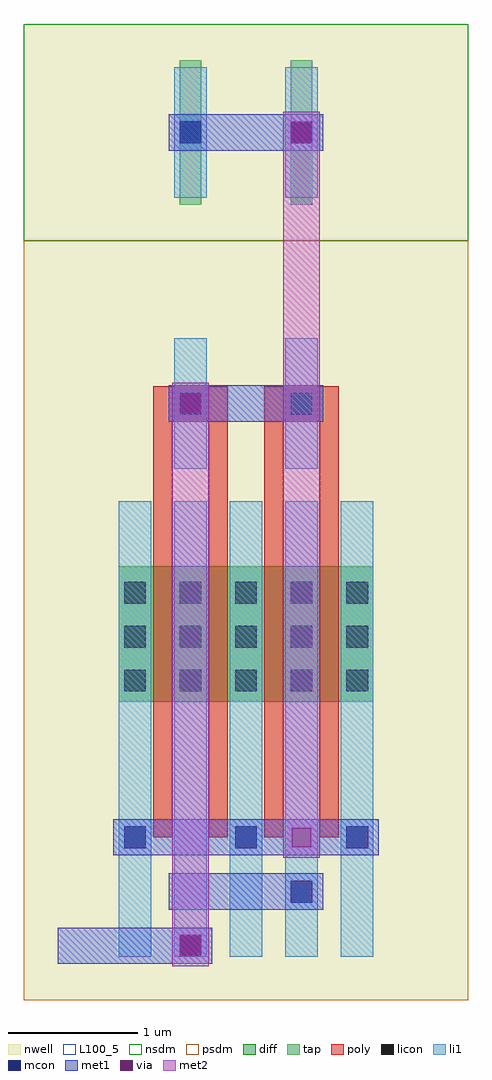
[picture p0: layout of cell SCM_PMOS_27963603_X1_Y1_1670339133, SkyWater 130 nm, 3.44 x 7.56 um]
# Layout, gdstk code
import gdstk
lib = gdstk.Library(unit=1e-6, precision=1e-09)
def R(c, l, rs):  # rectangles x0, y0, x1, y1
    for r in rs: c.add(gdstk.rectangle(r[:2], r[2:], *l))
def A(c, l, x, y, w, h, nx, ny, dx, dy):  # array of equal rectangles
    R(c, l, [(x+i*dx, y+j*dy, x+i*dx+w, y+j*dy+h) for i in range(nx) for j in range(ny)])
nwell = (64, 20)
diff = (65, 20)
tap = (65, 44)
poly = (66, 20)
licon = (66, 44)
li1 = (67, 20)
mcon = (67, 44)
met1 = (68, 20)
via = (68, 44)
met2 = (69, 20)
nsdm = (93, 44)
psdm = (94, 20)
L100_5 = (100, 5)

scm_pmos_27963603_x1_y1_ = lib.new_cell('SCM_PMOS_27963603_X1_Y1_1670339133')
R(scm_pmos_27963603_x1_y1_, nwell, [(0,0,3.44,7.56)])
R(scm_pmos_27963603_x1_y1_, diff, [(0.735,2.31,2.705,3.36)])
R(scm_pmos_27963603_x1_y1_, tap, [(1.205,6.16,1.375,7.28), (2.065,6.16,2.235,7.28)])
A(scm_pmos_27963603_x1_y1_, poly, 1, 1.26, 0.15, 3.36, 4, 1, 0.43, 0)
R(scm_pmos_27963603_x1_y1_, poly, [(1,4.485,1.58,4.755), (1.86,4.485,2.44,4.755)])
A(scm_pmos_27963603_x1_y1_, licon, 0.775, 2.39, 0.17, 0.17, 3, 3, 0.43, 0.34)
A(scm_pmos_27963603_x1_y1_, licon, 1.635, 2.39, 0.17, 0.17, 3, 3, 0.43, 0.34)
R(scm_pmos_27963603_x1_y1_, licon, [(1.205,4.535,1.375,4.705), (2.065,4.535,2.235,4.705), (1.205,6.635,1.375,6.805), (2.065,6.635,2.235,6.805)])
A(scm_pmos_27963603_x1_y1_, li1, 0.735, 0.335, 0.25, 3.53, 5, 1, 0.43, 0)
R(scm_pmos_27963603_x1_y1_, li1, [(1.165,4.115,1.415,5.125), (2.025,4.115,2.275,5.125), (1.165,6.215,1.415,7.225), (2.025,6.215,2.275,7.225)])
A(scm_pmos_27963603_x1_y1_, mcon, 0.775, 1.175, 0.17, 0.17, 3, 1, 0.86, 0)
R(scm_pmos_27963603_x1_y1_, mcon, [(1.205,0.335,1.375,0.505), (2.065,0.755,2.235,0.925), (1.205,4.535,1.375,4.705), (2.065,4.535,2.235,4.705), (1.205,6.635,1.375,6.805), (2.065,6.635,2.235,6.805)])
R(scm_pmos_27963603_x1_y1_, met1, [(0.26,0.28,1.46,0.56), (1.12,0.7,2.32,0.98), (0.69,1.12,2.75,1.4), (1.12,4.48,2.32,4.76), (1.12,6.58,2.32,6.86)])
R(scm_pmos_27963603_x1_y1_, via, [(1.215,0.345,1.365,0.495), (2.075,1.185,2.225,1.335), (1.215,4.545,1.365,4.695), (2.075,6.645,2.225,6.795)])
R(scm_pmos_27963603_x1_y1_, met2, [(1.15,0.26,1.43,4.78), (2.01,1.1,2.29,6.88)])
R(scm_pmos_27963603_x1_y1_, nsdm, [(0,5.88,3.44,7.56)])
R(scm_pmos_27963603_x1_y1_, psdm, [(0,0,3.44,5.88)])
R(scm_pmos_27963603_x1_y1_, L100_5, [(0,0,3.44,7.56)])

lib.write_gds('SCM_PMOS_27963603_X1_Y1_1670339133.gds')
